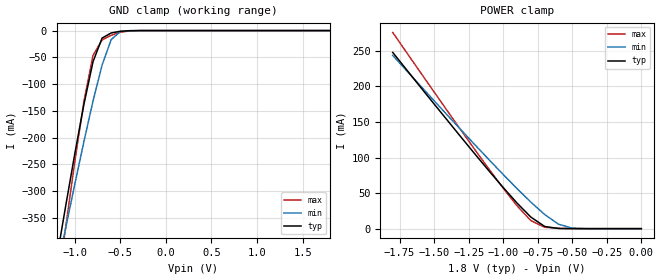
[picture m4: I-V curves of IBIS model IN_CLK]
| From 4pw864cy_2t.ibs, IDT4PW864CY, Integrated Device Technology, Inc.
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|   Model IN_CLK
[Model]   IN_CLK
Model_type   Input
Vinl =  0.37500V
Vinh =  1.42500V
C_comp   1.950000pF   1.950000pF   1.950000pF
[Temperature Range]   25.00000   0.11000k   0.000
[Voltage Range]   1.80000V   1.70000V   1.90000V
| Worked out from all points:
|   GND clamp passes 1 mA (typ) near -0.47 V on its own axis
|   POWER clamp passes 1 mA (typ) near -0.63 V on its own axis
[GND_clamp]
| voltage   I(typ)   I(min)   I(max)
-1.8V     -1.05A     -967.1mA   -1.281A
-1.2V     -428.6mA   -452.8mA   -494.2mA
-1.1V     -328.4mA   -369.5mA   -367.9mA
-1V       -230.8mA   -287.5mA   -245.7mA
-900mV    -138.3mA   -207.8mA   -132.6mA
-800mV    -58.34mA   -132mA     -46.35mA
-700mV    -13.98mA   -64.39mA   -17.53mA
-600mV    -4.426mA   -16.77mA   -8.796mA
-500mV    -1.273mA   -1.876mA   -3.12mA
-300mV    -33.83uA   -19.86uA   -122.4uA
1.8V      3.064nA    12.44nA    2.389nA
[POWER_clamp]
| voltage   I(typ)   I(min)   I(max)
-1.8V     247.8mA    243.6mA    275.9mA
-1.4V     151.3mA    158.7mA    164.4mA
-1.1V     80.56mA    96.37mA    82.87mA
-900mV    35.99mA    56.31mA    32.15mA
-800mV    16.32mA    37.31mA    11.38mA
-700mV    3.079mA    19.91mA    1.911mA
-600mV    249.7uA    6.316mA    485.3uA
-500mV    29.86uA    692.2uA    94.72uA
0V        3.064nA    2.22nA     2.641nA
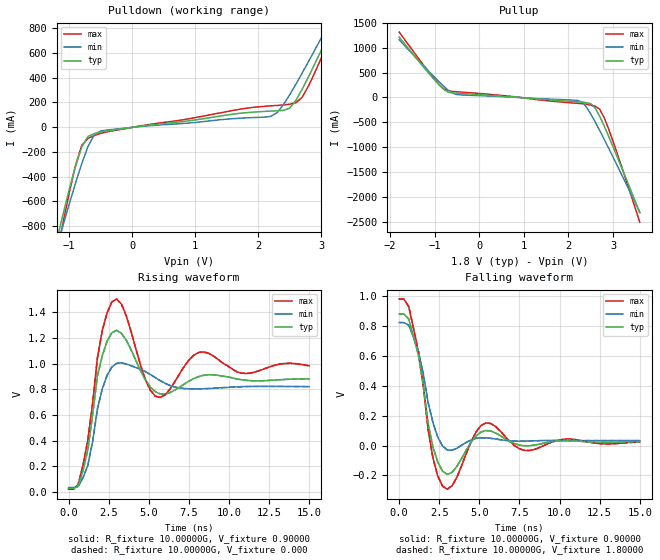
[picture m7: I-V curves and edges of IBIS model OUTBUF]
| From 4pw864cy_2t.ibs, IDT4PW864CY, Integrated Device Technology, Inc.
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|   Model OUTBUF
[Model]   OUTBUF
Model_type   Output
Polarity   Inverting
Vmeas =  0.90000V
C_comp   6.50000pF   5.40000pF   8.10000pF
[Temperature Range]   25.00000   0.11000k   0.000
[Voltage Range]   1.80000V   1.70000V   1.90000V
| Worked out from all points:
|   slope of the pulldown table from 0 to 0.27 V, typ, clamps not added: 14.4 ohm
|   slope of the pullup table from 0 to 0.27 V, typ, clamps not added: 16.8 ohm
|   rising waveform, R_fixture 10.00000G, V_fixture 0.90000: 20-80 % time 652ps typ, 683ps min, 676ps max; typ from 0.024 V to 0.881 V
|   rising waveform, R_fixture 10.00000G, V_fixture 0.000: 20-80 % time 652ps typ, 683ps min, 676ps max; typ from 0.024 V to 0.881 V
|   falling waveform, R_fixture 10.00000G, V_fixture 0.90000: 20-80 % time 800ps typ, 938ps min, 810ps max; typ from 0.878 V to 0.025 V
|   falling waveform, R_fixture 10.00000G, V_fixture 1.80000: 20-80 % time 800ps typ, 938ps min, 810ps max; typ from 0.878 V to 0.025 V
[Pulldown]
| voltage   I(typ)   I(min)   I(max)
-1.8V     -2.249A    -2.083A    -2.681A
-1.2V     -924.2mA   -979.2mA   -1.042A
-1.1V     -712.2mA   -800.6mA   -782.1mA
-900mV    -317.8mA   -455.8mA   -313.2mA
-700mV    -74.82mA   -155.5mA   -90.79mA
-500mV    -40.3mA    -31.13mA   -50.32mA
2.2V      129.7mA    86.66mA    172.3mA
2.5V      153.8mA    262.1mA    185.3mA
2.7V      308.8mA    439.6mA    243.5mA
3.1V      729.1mA    816.7mA    675.9mA
3.2V      838.4mA    912.9mA    795.5mA
3.6V      1.281A     1.301A     1.283A
[Pullup]
| voltage   I(typ)   I(min)   I(max)
-1.8V     1.216A     1.164A     1.317A
-1V       349.2mA    401.1mA    362.5mA
-700mV    108.2mA    147.1mA    135.1mA
-500mV    85.41mA    57.94mA    113.8mA
2.2V      -86.37mA   -60.02mA   -117.8mA
2.3V      -92.92mA   -91.47mA   -124.9mA
2.5V      -127.4mA   -331.9mA   -153.3mA
2.6V      -215.7mA   -493.6mA   -177.3mA
2.7V      -379.1mA   -664.3mA   -235.5mA
2.8V      -572.7mA   -840.1mA   -404.6mA
3V        -993mA     -1.2A      -883.3mA
3.6V      -2.323A    -2.312A    -2.512A
[Ramp]
| variable   typ   min   max
dV/dt_r   0.51427/0.58900n   0.47288/0.73606n   0.57814/0.58311n
dV/dt_f   0.51151/0.79054n   0.47284/0.97415n   0.57245/0.78210n
R_load = 10.00000G
[Rising Waveform]
R_fixture = 10.00000G
V_fixture = 0.90000
V_fixture_min = 0.85000
V_fixture_max = 0.95000
| time   V(typ)   V(min)   V(max)
0s        23.98mV    32.86mV    20.63mV
600ps     46.27mV    42.03mV    56.23mV
1.2ns     327.3mV    207.2mV    401.9mV
1.8ns     905.2mV    647.3mV    1.046V
2.1ns     1.061V     802.2mV    1.257V
3ns       1.26V      1.003V     1.504V
5.4ns     781.7mV    892mV      747.4mV
8.1ns     898.9mV    803.5mV    1.087V
10.8ns    874.4mV    820.7mV    926mV
15ns      881.1mV    821mV      983.5mV
[Rising Waveform]
R_fixture = 10.00000G
V_fixture = 0.000
V_fixture_min = 0.000
V_fixture_max = 0.000
| time   V(typ)   V(min)   V(max)
0s        23.98mV    32.86mV    20.63mV
600ps     46.27mV    42.03mV    56.23mV
1.2ns     327.3mV    207.2mV    401.9mV
1.8ns     905.2mV    647.3mV    1.046V
2.1ns     1.061V     802.2mV    1.257V
3ns       1.26V      1.003V     1.504V
5.4ns     781.7mV    892mV      747.4mV
8.1ns     898.9mV    803.5mV    1.087V
10.8ns    874.4mV    820.7mV    926mV
15ns      881.1mV    821mV      983.5mV
[Falling Waveform]
R_fixture = 10.00000G
V_fixture = 0.90000
V_fixture_min = 0.85000
V_fixture_max = 0.95000
| time   V(typ)   V(min)   V(max)
0s        877.6mV    821mV      977.7mV
600ps     843.8mV    802.8mV    926.5mV
1.2ns     602.6mV    626.8mV    628.2mV
2.1ns     -7.425mV   155.8mV    -79.92mV
3ns       -192.5mV   -29.62mV   -291.3mV
4.8ns     64.46mV    48.2mV     91.69mV
5.4ns     100.1mV    51mV       150.5mV
7.8ns     -1.779mV   29.39mV    -32.09mV
10.5ns    33.07mV    33.42mV    43.72mV
15ns      25mV       32.94mV    23.99mV
[Falling Waveform]
R_fixture = 10.00000G
V_fixture = 1.80000
V_fixture_min = 1.70000
V_fixture_max = 1.90000
| time   V(typ)   V(min)   V(max)
0s        877.6mV    821mV      977.7mV
600ps     843.8mV    802.8mV    926.5mV
1.2ns     602.6mV    626.8mV    628.2mV
2.1ns     -7.425mV   155.8mV    -79.92mV
3ns       -192.5mV   -29.62mV   -291.3mV
4.8ns     64.46mV    48.2mV     91.69mV
5.4ns     100.1mV    51mV       150.5mV
7.8ns     -1.779mV   29.39mV    -32.09mV
10.5ns    33.07mV    33.42mV    43.72mV
15ns      25mV       32.94mV    23.99mV
